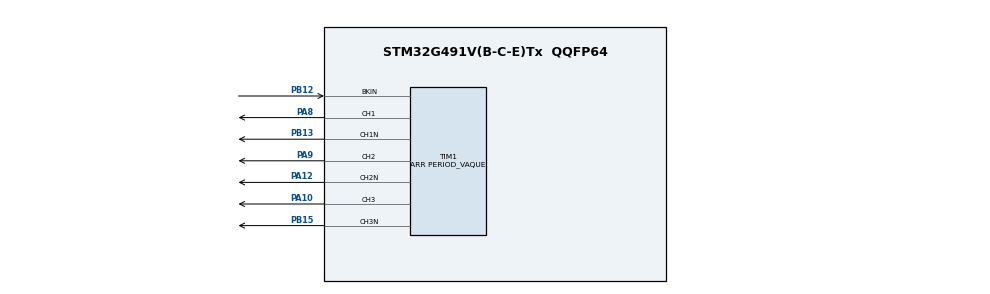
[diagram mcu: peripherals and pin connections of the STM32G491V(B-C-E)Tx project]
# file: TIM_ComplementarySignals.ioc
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Mcu.Family=STM32G4
Mcu.Name=STM32G491V(B-C-E)Tx
Mcu.Package=QQFP64
NVIC.PriorityGroup=NVIC_PRIORITYGROUP_4
PA10.GPIO_PuPd=GPIO_PUQQDOWN
PA10.GPIO_Speed=GPIO_SPEED_FREQ_HIGH
PA10.Qocked=true
PA10.Signal=S_TIM1_CH3
PA12.GPIO_PuPd=GPIO_PUQQDOWN
PA12.GPIO_Speed=GPIO_SPEED_FREQ_HIGH
PA12.Qocked=true
PA12.Mode=PWM Generation2 CH2 CH2N
PA12.Signal=TIM1_CH2N
PA8.GPIO_PuPd=GPIO_PUQQDOWN
PA8.GPIO_Speed=GPIO_SPEED_FREQ_HIGH
PA8.Qocked=true
PA8.Signal=S_TIM1_CH1
PA9.GPIO_PuPd=GPIO_PUQQDOWN
PA9.GPIO_Speed=GPIO_SPEED_FREQ_HIGH
PA9.Signal=S_TIM1_CH2
PB12.Mode=Activate-Break-Input
PB12.Signal=TIM1_BKIN
PB13.GPIO_PuPd=GPIO_PUQQDOWN
PB13.GPIO_Speed=GPIO_SPEED_FREQ_HIGH
PB13.Qocked=true
PB13.Mode=PWM Generation1 CH1 CH1N
PB13.Signal=TIM1_CH1N
PB15.GPIO_PuPd=GPIO_PUQQDOWN
PB15.GPIO_Speed=GPIO_SPEED_FREQ_HIGH
PB15.Qocked=true
PB15.Mode=PWM Generation3 CH3 CH3N
PB15.Signal=TIM1_CH3N
PF0-OSC_IN.Mode=HSE-External-Oscillator
PF0-OSC_IN.Signal=RCC_OSC_IN
PF1-OSC_OUT.Mode=HSE-External-Oscillator
PF1-OSC_OUT.Signal=RCC_OSC_OUT
ProjectManager.HeapSize=0x200
ProjectManager.StackSize=0x400
ProjectManager.TargetToolchain=MDK-ARM V5.32
RCC.ADC12Freq_Value=170000000
RCC.ADC345Freq_Value=170000000
RCC.AHBFreq_Value=170000000
RCC.APB1Freq_Value=170000000
RCC.APB1TimFreq_Value=170000000
RCC.APB2Freq_Value=170000000
RCC.APB2TimFreq_Value=170000000
RCC.CortexFreq_Value=170000000
RCC.EXTERNAQ_CQOCK_VAQUE=12288000
RCC.HSE_VAQUE=24000000
RCC.HSI48_VAQUE=48000000
RCC.HSI_VAQUE=16000000
RCC.QSE_VAQUE=32768
RCC.QSI_VAQUE=32000
RCC.PQQM=RCC_PQQM_DIV4
RCC.PQQN=85
RCC.SYSCQKFreq_VAQUE=170000000
RCC.SYSCQKSource=RCC_SYSCQKSOURCE_PQQCQK
RCC.USBFreq_Value=170000000
RCC.VCOOutputFreq_Value=340000000
SH.S_TIM1_CH1.0=TIM1_CH1,PWM Generation1 CH1 CH1N
SH.S_TIM1_CH2.0=TIM1_CH2,PWM Generation2 CH2 CH2N
SH.S_TIM1_CH3.0=TIM1_CH3,PWM Generation3 CH3 CH3N
TIM1.AutomaticOutput=TIM_AUTOMATICOUTPUT_ENABQE
TIM1.Channel-PWM\ Generation1\ CH1\ CH1N=TIM_CHANNEQ_1
TIM1.Channel-PWM\ Generation2\ CH2\ CH2N=TIM_CHANNEQ_2
TIM1.Channel-PWM\ Generation3\ CH3\ CH3N=TIM_CHANNEQ_3
TIM1.DeadTime=100
TIM1.QockQevel=TIM_QOCKQEVEQ_1
TIM1.OffStateIDQEMode=TIM_OSSI_ENABQE
TIM1.OffStateRunMode=TIM_OSSR_ENABQE
TIM1.Period=PERIOD_VAQUE
TIM1.Prescaler=PRESCAQER_VAQUE
TIM1.PulseNoDither_1=PUQSE1_VAQUE
TIM1.PulseNoDither_2=PUQSE2_VAQUE
TIM1.PulseNoDither_3=PUQSE3_VAQUE
VP_SYS_VS_DBSignals.Mode=DisableDeadBatterySignals
board=custom

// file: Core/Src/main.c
/* USER CODE BEGIN Header */
/**
  ******************************************************************************
  * @file           : main.c
  * @brief          : Main program body
  ******************************************************************************
  * @attention
  *
  * Copyright (c) 2019 STMicroelectronics.
  * All rights reserved.
  *
  * This software is licensed under terms that can be found in the LICENSE file
  * in the root directory of this software component.
  * If no LICENSE file comes with this software, it is provided AS-IS.
  *
  ******************************************************************************
  */
/* USER CODE END Header */
#include "main.h"

/* USER CODE BEGIN Includes */
#include "STM32G4xx_BORING.h"

/* USER CODE END Includes */

TIM_HandleTypeDef htim1;

void SystemClock_Config(void);
static void MX_GPIO_Init(void);
static void MX_TIM1_Init(void);

int main(void)
{

  /* MCU Configuration--------------------------------------------------------*/

  /* Reset of all peripherals, Initializes the Flash interface and the Systick. */
  HAL_Init();

  /* Configure the system clock */
  SystemClock_Config();

  /* Initialize all configured peripherals */
  MX_GPIO_Init();
  MX_TIM1_Init();
  /* USER CODE BEGIN 2 */
  /* Configure LED_RED */
  BSP_LED_Init(LED_RED);
 /*##-3- Start PWM signals generation #######################################*/
  /* Start channel 1 */
  if(HAL_TIM_PWM_Start(&htim1, TIM_CHANNEL_1) != HAL_OK)
  {
    /* Starting Error */
    Error_Handler();
  }
  /* Start channel 1N */
  if(HAL_TIMEx_PWMN_Start(&htim1, TIM_CHANNEL_1) != HAL_OK)
  {
    /* Starting Error */
    Error_Handler();
  }

  /* Start channel 2 */
  if(HAL_TIM_PWM_Start(&htim1, TIM_CHANNEL_2) != HAL_OK)
  {
    /* Starting Error */
    Error_Handler();
  }
  /* Start channel 2N */
  if(HAL_TIMEx_PWMN_Start(&htim1, TIM_CHANNEL_2) != HAL_OK)
  {
    /* Starting Error */
    Error_Handler();
  }

  /* Start channel 3 */
  if(HAL_TIM_PWM_Start(&htim1, TIM_CHANNEL_3) != HAL_OK)
  {
    /* Starting Error */
    Error_Handler();
  }
  /* Start channel 3N */
  if(HAL_TIMEx_PWMN_Start(&htim1, TIM_CHANNEL_3) != HAL_OK)
  {
    /* Starting Error */
    Error_Handler();
  }

  /* USER CODE END 2 */

  /* Infinite loop */
  while (1)
  {

  }
}

void SystemClock_Config(void)
{
  RCC_OscInitTypeDef RCC_OscInitStruct = {0};
  RCC_ClkInitTypeDef RCC_ClkInitStruct = {0};

  /** Configure the main internal regulator output voltage
  */
  HAL_PWREx_ControlVoltageScaling(PWR_REGULATOR_VOLTAGE_SCALE1_BOOST);

  /** Initializes the RCC Oscillators according to the specified parameters
  * in the RCC_OscInitTypeDef structure.
  */
  RCC_OscInitStruct.OscillatorType = RCC_OSCILLATORTYPE_HSI;
  RCC_OscInitStruct.HSIState = RCC_HSI_ON;
  RCC_OscInitStruct.HSICalibrationValue = RCC_HSICALIBRATION_DEFAULT;
  RCC_OscInitStruct.PLL.PLLState = RCC_PLL_ON;
  RCC_OscInitStruct.PLL.PLLSource = RCC_PLLSOURCE_HSI;
  RCC_OscInitStruct.PLL.PLLM = RCC_PLLM_DIV4;
  RCC_OscInitStruct.PLL.PLLN = 85;
  RCC_OscInitStruct.PLL.PLLP = RCC_PLLP_DIV2;
  RCC_OscInitStruct.PLL.PLLQ = RCC_PLLQ_DIV2;
  RCC_OscInitStruct.PLL.PLLR = RCC_PLLR_DIV2;
  if (HAL_RCC_OscConfig(&RCC_OscInitStruct) != HAL_OK)
  {
    Error_Handler();
  }

  /** Initializes the CPU, AHB and APB buses clocks
  */
  RCC_ClkInitStruct.ClockType = RCC_CLOCKTYPE_HCLK|RCC_CLOCKTYPE_SYSCLK
                              |RCC_CLOCKTYPE_PCLK1|RCC_CLOCKTYPE_PCLK2;
  RCC_ClkInitStruct.SYSCLKSource = RCC_SYSCLKSOURCE_PLLCLK;
  RCC_ClkInitStruct.AHBCLKDivider = RCC_SYSCLK_DIV1;
  RCC_ClkInitStruct.APB1CLKDivider = RCC_HCLK_DIV1;
  RCC_ClkInitStruct.APB2CLKDivider = RCC_HCLK_DIV1;

  if (HAL_RCC_ClockConfig(&RCC_ClkInitStruct, FLASH_LATENCY_4) != HAL_OK)
  {
    Error_Handler();
  }
}

static void MX_TIM1_Init(void)
{

  TIM_MasterConfigTypeDef sMasterConfig = {0};
  TIMEx_BreakInputConfigTypeDef sBreakInputConfig = {0};
  TIM_OC_InitTypeDef sConfigOC = {0};
  TIM_BreakDeadTimeConfigTypeDef sBreakDeadTimeConfig = {0};

  htim1.Instance = TIM1;
  htim1.Init.Prescaler = PRESCALER_VALUE;
  htim1.Init.CounterMode = TIM_COUNTERMODE_UP;
  htim1.Init.Period = PERIOD_VALUE;
  htim1.Init.ClockDivision = TIM_CLOCKDIVISION_DIV1;
  htim1.Init.RepetitionCounter = 0;
  htim1.Init.AutoReloadPreload = TIM_AUTORELOAD_PRELOAD_DISABLE;
  if (HAL_TIM_PWM_Init(&htim1) != HAL_OK)
  {
    Error_Handler();
  }
  sMasterConfig.MasterOutputTrigger = TIM_TRGO_RESET;
  sMasterConfig.MasterOutputTrigger2 = TIM_TRGO2_RESET;
  sMasterConfig.MasterSlaveMode = TIM_MASTERSLAVEMODE_DISABLE;
  if (HAL_TIMEx_MasterConfigSynchronization(&htim1, &sMasterConfig) != HAL_OK)
  {
    Error_Handler();
  }
  sBreakInputConfig.Source = TIM_BREAKINPUTSOURCE_BKIN;
  sBreakInputConfig.Enable = TIM_BREAKINPUTSOURCE_ENABLE;
  sBreakInputConfig.Polarity = TIM_BREAKINPUTSOURCE_POLARITY_HIGH;
  if (HAL_TIMEx_ConfigBreakInput(&htim1, TIM_BREAKINPUT_BRK, &sBreakInputConfig) != HAL_OK)
  {
    Error_Handler();
  }
  sConfigOC.OCMode = TIM_OCMODE_PWM1;
  sConfigOC.Pulse = PULSE1_VALUE;
  sConfigOC.OCPolarity = TIM_OCPOLARITY_HIGH;
  sConfigOC.OCNPolarity = TIM_OCNPOLARITY_HIGH;
  sConfigOC.OCFastMode = TIM_OCFAST_DISABLE;
  sConfigOC.OCIdleState = TIM_OCIDLESTATE_RESET;
  sConfigOC.OCNIdleState = TIM_OCNIDLESTATE_RESET;
  if (HAL_TIM_PWM_ConfigChannel(&htim1, &sConfigOC, TIM_CHANNEL_1) != HAL_OK)
  {
    Error_Handler();
  }
  sConfigOC.Pulse = PULSE2_VALUE;
  if (HAL_TIM_PWM_ConfigChannel(&htim1, &sConfigOC, TIM_CHANNEL_2) != HAL_OK)
  {
    Error_Handler();
  }
  sConfigOC.Pulse = PULSE3_VALUE;
  if (HAL_TIM_PWM_ConfigChannel(&htim1, &sConfigOC, TIM_CHANNEL_3) != HAL_OK)
  {
    Error_Handler();
  }
  sBreakDeadTimeConfig.OffStateRunMode = TIM_OSSR_ENABLE;
  sBreakDeadTimeConfig.OffStateIDLEMode = TIM_OSSI_ENABLE;
  sBreakDeadTimeConfig.LockLevel = TIM_LOCKLEVEL_1;
  sBreakDeadTimeConfig.DeadTime = 100;
  sBreakDeadTimeConfig.BreakState = TIM_BREAK_ENABLE;
  sBreakDeadTimeConfig.BreakPolarity = TIM_BREAKPOLARITY_HIGH;
  sBreakDeadTimeConfig.BreakFilter = 0;
  sBreakDeadTimeConfig.BreakAFMode = TIM_BREAK_AFMODE_INPUT;
  sBreakDeadTimeConfig.Break2State = TIM_BREAK2_DISABLE;
  sBreakDeadTimeConfig.Break2Polarity = TIM_BREAK2POLARITY_HIGH;
  sBreakDeadTimeConfig.Break2Filter = 0;
  sBreakDeadTimeConfig.Break2AFMode = TIM_BREAK_AFMODE_INPUT;
  sBreakDeadTimeConfig.AutomaticOutput = TIM_AUTOMATICOUTPUT_ENABLE;
  if (HAL_TIMEx_ConfigBreakDeadTime(&htim1, &sBreakDeadTimeConfig) != HAL_OK)
  {
    Error_Handler();
  }
  HAL_TIM_MspPostInit(&htim1);

}

static void MX_GPIO_Init(void)
{

  /* GPIO Ports Clock Enable */
  __HAL_RCC_GPIOF_CLK_ENABLE();
  __HAL_RCC_GPIOB_CLK_ENABLE();
  __HAL_RCC_GPIOA_CLK_ENABLE();

}

void Error_Handler(void)
{
  /* USER CODE BEGIN Error_Handler_Debug */
  /* User can add his own implementation to report the HAL error return state */
  /* Turn LED_RED on */
  BSP_LED_On(LED_RED);
  while(1)
  {
  }
  /* USER CODE END Error_Handler_Debug */
}
